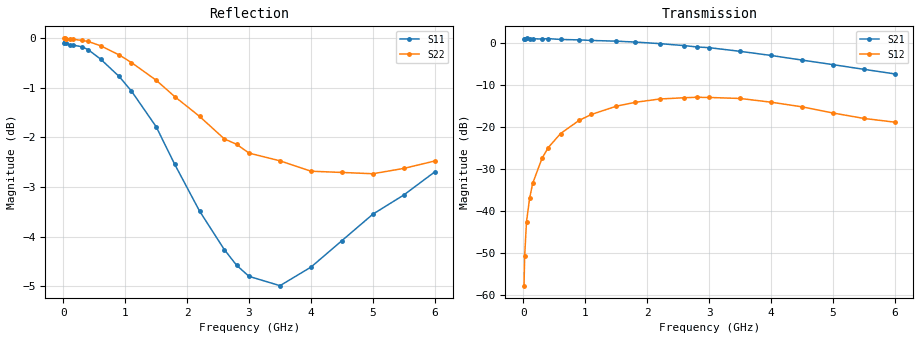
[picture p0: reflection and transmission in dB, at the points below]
! SIEMENS Small Signal Semiconductors
! BFP181
! Si NPN RF Bipolar Junction Transistor in SOT143
! VCE = 3 V  IC = 0.3 mA
! Common Emitter S-Parameters:  March  1996
# GHz  S  MA  R  50
!  f  S11  S21  S12  S22
! GHz  MAG  ANG  MAG  ANG  MAG  ANG  MAG  ANG
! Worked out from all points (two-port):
!   36 points, 10 MHz to 6 GHz, reference 50 ohm
!   highest |S21| = 1.15 dB at 50 MHz (marker M1); lowest = -7.3 dB at 6 GHz (marker M2)
!   |S21| within 3 dB of the highest: start of sweep to 3.453 GHz
!   lowest |S11| = -5.0 dB at 3.5 GHz (marker M3), VSWR 3.58, Z = 14.1 + j5.08 ohm
!   |S11| at or under -10 dB: nowhere
!   |S22| runs from -2.7 to 0.0 dB; largest |S21 - S12| = 1.1
!   S11 on the Smith chart (normalised r, x): 10 MHz: open; 900 MHz: 0.32, -2.46; 1.8 GHz: 0.28, -0.95; 2.8 GHz: 0.27, -0.25; 4 GHz: 0.29, +0.31; 6 GHz: 0.31, +0.97
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0.01  0.9878 -0.7  1.115 179.8  0.0013 86.3  0.9996 -0.1
0.02  0.9928 -1.1  1.134 179.6  0.0029 88.3  0.9993 -0.4
0.05  0.9898 -2.2  1.142 177.5  0.0075 91.5  0.9992 -1.2
0.1  0.9839 -4.9  1.118 175.1  0.0142 86.0  0.9986 -2.4
0.15  0.9844 -7.4  1.13 172.5  0.0215 84.5  0.9977 -3.6
0.3  0.9802 -14.6  1.122 165.4  0.0425 79.5  0.9948 -7.2
0.4  0.9738 -19.4  1.134 159.5  0.0571 75.9  0.9925 -9.6
0.6  0.9528 -28.9  1.109 149.8  0.084 68.6  0.9826 -14.3
0.9  0.9152 -43.7  1.095 135.3  0.1207 57.7  0.962 -21.3
1.1  0.8846 -53.5  1.079 125.9  0.142 50.9  0.9451 -25.7
1.5  0.8142 -74.2  1.057 108.1  0.1779 38.3  0.907 -33.9
1.8  0.7461 -90.5  1.033 94.3  0.1975 29.4  0.8732 -39.6
2.2  0.6697 -113.3  0.989 77.4  0.2167 17.9  0.8341 -46.9
2.6  0.6124 -137.9  0.936 62.1  0.2244 7.8  0.7917 -53.5
2.8  0.5904 -150.2  0.903 53.7  0.2272 2.5  0.7817 -56.9
3  0.5755 -163.0  0.885 46.3  0.226 -2.6  0.766 -60.2
3.5  0.5632 167.4  0.801 28.8  0.22 -13.4  0.7524 -68.5
4  0.588 143.5  0.715 13.7  0.1987 -22.5  0.7345 -78.0
4.5  0.6252 124.1  0.63 0.5  0.175 -29.6  0.7324 -88.5
5  0.6648 109.4  0.556 -9.6  0.1477 -32.9  0.7302 -99.4
5.5  0.6951 97.9  0.489 -19.4  0.1273 -30.6  0.7393 -110.3
6  0.7333 88.9  0.431 -26.5  0.1149 -25.6  0.7521 -121.7
